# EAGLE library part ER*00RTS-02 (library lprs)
Easy-Radio '02' (2nd Generation Modules) Transceiver Source: http://www.lprs.co.uk/pdf_directory/2386mylprs1132229147er-datasheet-2.3-sept-05.pdf

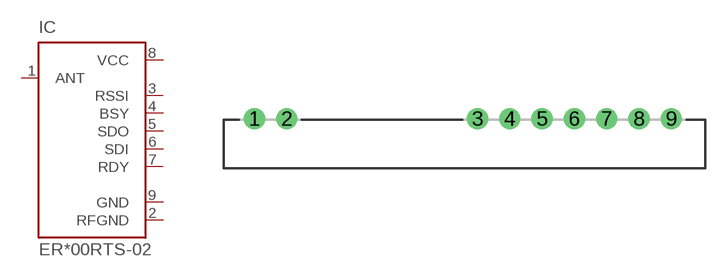
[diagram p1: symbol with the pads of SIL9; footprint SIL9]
Designator prefix IC

## ER400RTS-02 (MPN: ER400RS; OC_FARNELL: 5096522; OC_NEWARK: 13J9292), ER900RTS-02 (MPN: ER900RS; OC_FARNELL: 5096546; OC_NEWARK: 13J9297)  [SIL9]
1  ANT  in
2  RFGND  in
3  RSSI  out
4  BSY
5  SDO  out
6  SDI
7  RDY
8  VCC  pwr
9  GND  pwr

## Footprint SIL9 (pad centres in mm)
Single In ine 9 leads ER Receiver Source: http://www.lprs.co.uk/pdf_directory/2386mylprs1132229147er-datasheet-2.3-sept-05.pdf
drill 1 pad 1.676 round: 1 -16.51,2.54; 2 -13.97,2.54; 3 1.03,2.54; 4 3.57,2.54; 5 6.11,2.54; 6 8.65,2.54; 7 11.19,2.54; 8 13.73,2.54; 9 16.27,2.54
